VERSION 5.7 ;
  NOWIREEXTENSIONATPIN ON ;
  DIVIDERCHAR "/" ;
  BUSBITCHARS "[]" ;
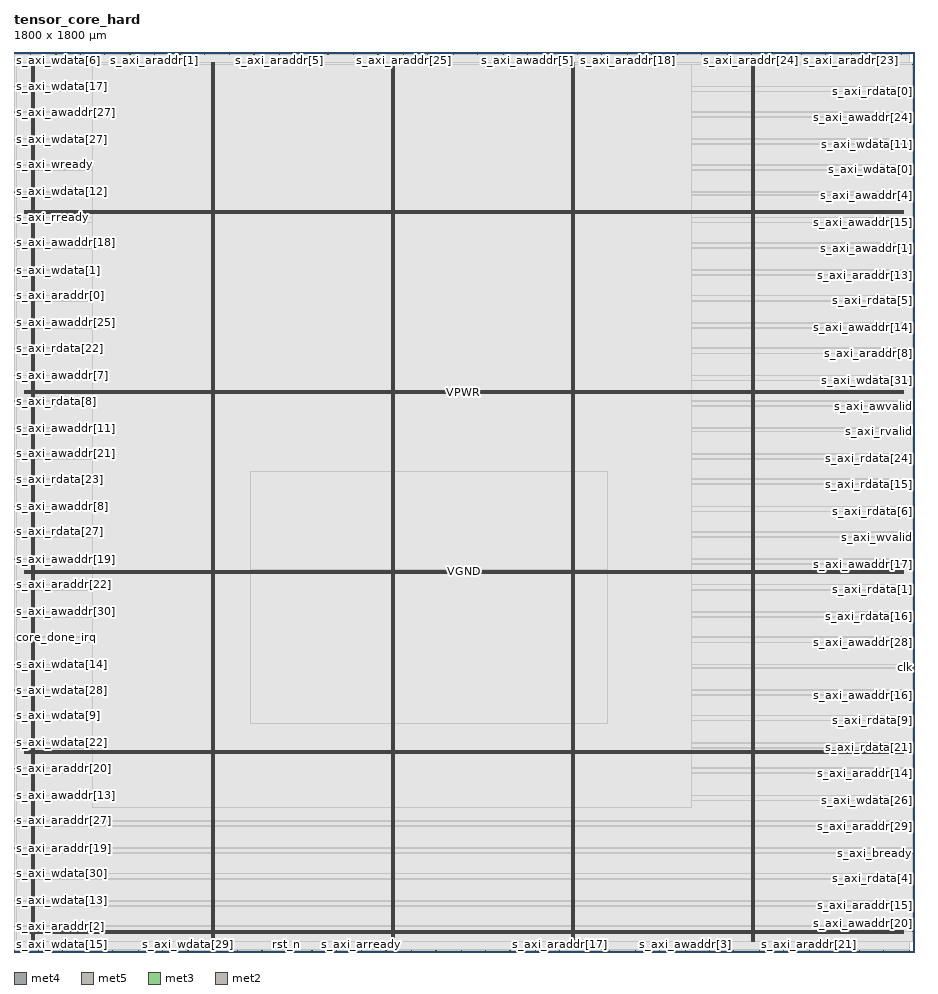
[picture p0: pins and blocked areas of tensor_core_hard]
MACRO tensor_core_hard
  CLASS BLOCK ;
  FOREIGN tensor_core_hard ;
  ORIGIN 0.000 0.000 ;
  SIZE 1800.000 BY 1800.000 ;
  PIN VGND
    DIRECTION INOUT ;
    USE GROUND ;
    PORT
      LAYER met4 ;
        RECT 39.060 21.520 40.660 1779.120 ;
    END
    PORT
      LAYER met4 ;
        RECT 399.060 21.520 400.660 1779.120 ;
    END
    PORT
      LAYER met4 ;
        RECT 759.060 21.520 760.660 1779.120 ;
    END
    PORT
      LAYER met4 ;
        RECT 1119.060 21.520 1120.660 1779.120 ;
    END
    PORT
      LAYER met4 ;
        RECT 1479.060 21.520 1480.660 1779.120 ;
    END
    PORT
      LAYER met5 ;
        RECT 20.000 40.910 1779.980 42.510 ;
    END
    PORT
      LAYER met5 ;
        RECT 20.000 400.910 1779.980 402.510 ;
    END
    PORT
      LAYER met5 ;
        RECT 20.000 760.910 1779.980 762.510 ;
    END
    PORT
      LAYER met5 ;
        RECT 20.000 1120.910 1779.980 1122.510 ;
    END
    PORT
      LAYER met5 ;
        RECT 20.000 1480.910 1779.980 1482.510 ;
    END
  END VGND
  PIN VPWR
    DIRECTION INOUT ;
    USE POWER ;
    PORT
      LAYER met4 ;
        RECT 35.760 21.520 37.360 1779.120 ;
    END
    PORT
      LAYER met4 ;
        RECT 395.760 21.520 397.360 1779.120 ;
    END
    PORT
      LAYER met4 ;
        RECT 755.760 21.520 757.360 1779.120 ;
    END
    PORT
      LAYER met4 ;
        RECT 1115.760 21.520 1117.360 1779.120 ;
    END
    PORT
      LAYER met4 ;
        RECT 1475.760 21.520 1477.360 1779.120 ;
    END
    PORT
      LAYER met5 ;
        RECT 20.000 37.610 1779.980 39.210 ;
    END
    PORT
      LAYER met5 ;
        RECT 20.000 397.610 1779.980 399.210 ;
    END
    PORT
      LAYER met5 ;
        RECT 20.000 757.610 1779.980 759.210 ;
    END
    PORT
      LAYER met5 ;
        RECT 20.000 1117.610 1779.980 1119.210 ;
    END
    PORT
      LAYER met5 ;
        RECT 20.000 1477.610 1779.980 1479.210 ;
    END
  END VPWR
  PIN clk
    DIRECTION INPUT ;
    USE SIGNAL ;
    ANTENNAGATEAREA 1.286700 ;
    ANTENNADIFFAREA 0.434700 ;
    PORT
      LAYER met3 ;
        RECT 1796.000 567.840 1800.000 568.440 ;
    END
  END clk
  PIN core_done_irq
    DIRECTION OUTPUT TRISTATE ;
    USE SIGNAL ;
    ANTENNADIFFAREA 0.795200 ;
    PORT
      LAYER met3 ;
        RECT 0.000 629.040 4.000 629.640 ;
    END
  END core_done_irq
  PIN rst_n
    DIRECTION INPUT ;
    USE SIGNAL ;
    ANTENNAGATEAREA 1.286700 ;
    ANTENNADIFFAREA 0.434700 ;
    PORT
      LAYER met2 ;
        RECT 544.270 0.000 544.550 4.000 ;
    END
  END rst_n
  PIN s_axi_araddr[0]
    DIRECTION INPUT ;
    USE SIGNAL ;
    ANTENNAGATEAREA 0.860700 ;
    ANTENNADIFFAREA 0.434700 ;
    PORT
      LAYER met3 ;
        RECT 0.000 1312.440 4.000 1313.040 ;
    END
  END s_axi_araddr[0]
  PIN s_axi_araddr[10]
    DIRECTION INPUT ;
    USE SIGNAL ;
    PORT
      LAYER met3 ;
        RECT 0.000 1785.040 4.000 1785.640 ;
    END
  END s_axi_araddr[10]
  PIN s_axi_araddr[11]
    DIRECTION INPUT ;
    USE SIGNAL ;
    PORT
      LAYER met2 ;
        RECT 83.810 1796.000 84.090 1800.000 ;
    END
  END s_axi_araddr[11]
  PIN s_axi_araddr[12]
    DIRECTION INPUT ;
    USE SIGNAL ;
    PORT
      LAYER met2 ;
        RECT 495.970 0.000 496.250 4.000 ;
    END
  END s_axi_araddr[12]
  PIN s_axi_araddr[13]
    DIRECTION INPUT ;
    USE SIGNAL ;
    PORT
      LAYER met3 ;
        RECT 1796.000 1353.240 1800.000 1353.840 ;
    END
  END s_axi_araddr[13]
  PIN s_axi_araddr[14]
    DIRECTION INPUT ;
    USE SIGNAL ;
    PORT
      LAYER met3 ;
        RECT 1796.000 357.040 1800.000 357.640 ;
    END
  END s_axi_araddr[14]
  PIN s_axi_araddr[15]
    DIRECTION INPUT ;
    USE SIGNAL ;
    ANTENNAGATEAREA 1.424700 ;
    ANTENNADIFFAREA 0.434700 ;
    PORT
      LAYER met3 ;
        RECT 1796.000 91.840 1800.000 92.440 ;
    END
  END s_axi_araddr[15]
  PIN s_axi_araddr[16]
    DIRECTION INPUT ;
    USE SIGNAL ;
    PORT
      LAYER met2 ;
        RECT 795.430 0.000 795.710 4.000 ;
    END
  END s_axi_araddr[16]
  PIN s_axi_araddr[17]
    DIRECTION INPUT ;
    USE SIGNAL ;
    PORT
      LAYER met2 ;
        RECT 1091.670 0.000 1091.950 4.000 ;
    END
  END s_axi_araddr[17]
  PIN s_axi_araddr[18]
    DIRECTION INPUT ;
    USE SIGNAL ;
    PORT
      LAYER met2 ;
        RECT 1226.910 1796.000 1227.190 1800.000 ;
    END
  END s_axi_araddr[18]
  PIN s_axi_araddr[19]
    DIRECTION INPUT ;
    USE SIGNAL ;
    PORT
      LAYER met3 ;
        RECT 0.000 207.440 4.000 208.040 ;
    END
  END s_axi_araddr[19]
  PIN s_axi_araddr[1]
    DIRECTION INPUT ;
    USE SIGNAL ;
    ANTENNAGATEAREA 0.929700 ;
    ANTENNADIFFAREA 0.434700 ;
    PORT
      LAYER met2 ;
        RECT 280.230 1796.000 280.510 1800.000 ;
    END
  END s_axi_araddr[1]
  PIN s_axi_araddr[20]
    DIRECTION INPUT ;
    USE SIGNAL ;
    PORT
      LAYER met3 ;
        RECT 0.000 367.240 4.000 367.840 ;
    END
  END s_axi_araddr[20]
  PIN s_axi_araddr[21]
    DIRECTION INPUT ;
    USE SIGNAL ;
    PORT
      LAYER met2 ;
        RECT 1590.770 0.000 1591.050 4.000 ;
    END
  END s_axi_araddr[21]
  PIN s_axi_araddr[22]
    DIRECTION INPUT ;
    USE SIGNAL ;
    PORT
      LAYER met3 ;
        RECT 0.000 734.440 4.000 735.040 ;
    END
  END s_axi_araddr[22]
  PIN s_axi_araddr[23]
    DIRECTION INPUT ;
    USE SIGNAL ;
    PORT
      LAYER met2 ;
        RECT 1674.490 1796.000 1674.770 1800.000 ;
    END
  END s_axi_araddr[23]
  PIN s_axi_araddr[24]
    DIRECTION INPUT ;
    USE SIGNAL ;
    PORT
      LAYER met2 ;
        RECT 1474.850 1796.000 1475.130 1800.000 ;
    END
  END s_axi_araddr[24]
  PIN s_axi_araddr[25]
    DIRECTION INPUT ;
    USE SIGNAL ;
    PORT
      LAYER met2 ;
        RECT 779.330 1796.000 779.610 1800.000 ;
    END
  END s_axi_araddr[25]
  PIN s_axi_araddr[26]
    DIRECTION INPUT ;
    USE SIGNAL ;
    PORT
      LAYER met2 ;
        RECT 895.250 0.000 895.530 4.000 ;
    END
  END s_axi_araddr[26]
  PIN s_axi_araddr[27]
    DIRECTION INPUT ;
    USE SIGNAL ;
    PORT
      LAYER met3 ;
        RECT 0.000 261.840 4.000 262.440 ;
    END
  END s_axi_araddr[27]
  PIN s_axi_araddr[28]
    DIRECTION INPUT ;
    USE SIGNAL ;
    PORT
      LAYER met2 ;
        RECT 1622.970 1796.000 1623.250 1800.000 ;
    END
  END s_axi_araddr[28]
  PIN s_axi_araddr[29]
    DIRECTION INPUT ;
    USE SIGNAL ;
    PORT
      LAYER met3 ;
        RECT 1796.000 251.640 1800.000 252.240 ;
    END
  END s_axi_araddr[29]
  PIN s_axi_araddr[2]
    DIRECTION INPUT ;
    USE SIGNAL ;
    ANTENNAGATEAREA 1.424700 ;
    ANTENNADIFFAREA 0.434700 ;
    PORT
      LAYER met3 ;
        RECT 0.000 51.040 4.000 51.640 ;
    END
  END s_axi_araddr[2]
  PIN s_axi_araddr[30]
    DIRECTION INPUT ;
    USE SIGNAL ;
    PORT
      LAYER met2 ;
        RECT 1526.370 1796.000 1526.650 1800.000 ;
    END
  END s_axi_araddr[30]
  PIN s_axi_araddr[31]
    DIRECTION INPUT ;
    USE SIGNAL ;
    PORT
      LAYER met2 ;
        RECT 1722.790 1796.000 1723.070 1800.000 ;
    END
  END s_axi_araddr[31]
  PIN s_axi_araddr[3]
    DIRECTION INPUT ;
    USE SIGNAL ;
    ANTENNAGATEAREA 1.424700 ;
    ANTENNADIFFAREA 0.434700 ;
    PORT
      LAYER met2 ;
        RECT 180.410 1796.000 180.690 1800.000 ;
    END
  END s_axi_araddr[3]
  PIN s_axi_araddr[4]
    DIRECTION INPUT ;
    USE SIGNAL ;
    ANTENNAGATEAREA 1.424700 ;
    ANTENNADIFFAREA 0.434700 ;
    PORT
      LAYER met2 ;
        RECT 132.110 1796.000 132.390 1800.000 ;
    END
  END s_axi_araddr[4]
  PIN s_axi_araddr[5]
    DIRECTION INPUT ;
    USE SIGNAL ;
    ANTENNAGATEAREA 0.631200 ;
    ANTENNADIFFAREA 0.434700 ;
    PORT
      LAYER met2 ;
        RECT 531.390 1796.000 531.670 1800.000 ;
    END
  END s_axi_araddr[5]
  PIN s_axi_araddr[6]
    DIRECTION INPUT ;
    USE SIGNAL ;
    PORT
      LAYER met2 ;
        RECT 1143.190 0.000 1143.470 4.000 ;
    END
  END s_axi_araddr[6]
  PIN s_axi_araddr[7]
    DIRECTION INPUT ;
    USE SIGNAL ;
    PORT
      LAYER met2 ;
        RECT 943.550 0.000 943.830 4.000 ;
    END
  END s_axi_araddr[7]
  PIN s_axi_araddr[8]
    DIRECTION INPUT ;
    USE SIGNAL ;
    PORT
      LAYER met3 ;
        RECT 1796.000 1196.840 1800.000 1197.440 ;
    END
  END s_axi_araddr[8]
  PIN s_axi_araddr[9]
    DIRECTION INPUT ;
    USE SIGNAL ;
    PORT
      LAYER met2 ;
        RECT 1539.250 0.000 1539.530 4.000 ;
    END
  END s_axi_araddr[9]
  PIN s_axi_arready
    DIRECTION OUTPUT TRISTATE ;
    USE SIGNAL ;
    PORT
      LAYER met2 ;
        RECT 695.610 0.000 695.890 4.000 ;
    END
  END s_axi_arready
  PIN s_axi_arvalid
    DIRECTION INPUT ;
    USE SIGNAL ;
    ANTENNAGATEAREA 1.424700 ;
    ANTENNADIFFAREA 0.434700 ;
    PORT
      LAYER met2 ;
        RECT 627.990 1796.000 628.270 1800.000 ;
    END
  END s_axi_arvalid
  PIN s_axi_awaddr[0]
    DIRECTION INPUT ;
    USE SIGNAL ;
    ANTENNAGATEAREA 1.177200 ;
    ANTENNADIFFAREA 0.434700 ;
    PORT
      LAYER met2 ;
        RECT 927.450 1796.000 927.730 1800.000 ;
    END
  END s_axi_awaddr[0]
  PIN s_axi_awaddr[10]
    DIRECTION INPUT ;
    USE SIGNAL ;
    PORT
      LAYER met2 ;
        RECT 1490.950 0.000 1491.230 4.000 ;
    END
  END s_axi_awaddr[10]
  PIN s_axi_awaddr[11]
    DIRECTION INPUT ;
    USE SIGNAL ;
    PORT
      LAYER met3 ;
        RECT 0.000 1047.240 4.000 1047.840 ;
    END
  END s_axi_awaddr[11]
  PIN s_axi_awaddr[12]
    DIRECTION INPUT ;
    USE SIGNAL ;
    ANTENNAGATEAREA 0.860700 ;
    ANTENNADIFFAREA 0.434700 ;
    PORT
      LAYER met2 ;
        RECT 1175.390 1796.000 1175.670 1800.000 ;
    END
  END s_axi_awaddr[12]
  PIN s_axi_awaddr[13]
    DIRECTION INPUT ;
    USE SIGNAL ;
    ANTENNAGATEAREA 1.424700 ;
    ANTENNADIFFAREA 0.434700 ;
    PORT
      LAYER met3 ;
        RECT 0.000 312.840 4.000 313.440 ;
    END
  END s_axi_awaddr[13]
  PIN s_axi_awaddr[14]
    DIRECTION INPUT ;
    USE SIGNAL ;
    ANTENNAGATEAREA 0.593700 ;
    ANTENNADIFFAREA 0.434700 ;
    PORT
      LAYER met3 ;
        RECT 1796.000 1247.840 1800.000 1248.440 ;
    END
  END s_axi_awaddr[14]
  PIN s_axi_awaddr[15]
    DIRECTION INPUT ;
    USE SIGNAL ;
    ANTENNAGATEAREA 0.682200 ;
    ANTENNADIFFAREA 0.434700 ;
    PORT
      LAYER met3 ;
        RECT 1796.000 1458.640 1800.000 1459.240 ;
    END
  END s_axi_awaddr[15]
  PIN s_axi_awaddr[16]
    DIRECTION INPUT ;
    USE SIGNAL ;
    PORT
      LAYER met3 ;
        RECT 1796.000 513.440 1800.000 514.040 ;
    END
  END s_axi_awaddr[16]
  PIN s_axi_awaddr[17]
    DIRECTION INPUT ;
    USE SIGNAL ;
    PORT
      LAYER met3 ;
        RECT 1796.000 775.240 1800.000 775.840 ;
    END
  END s_axi_awaddr[17]
  PIN s_axi_awaddr[18]
    DIRECTION INPUT ;
    USE SIGNAL ;
    PORT
      LAYER met3 ;
        RECT 0.000 1417.840 4.000 1418.440 ;
    END
  END s_axi_awaddr[18]
  PIN s_axi_awaddr[19]
    DIRECTION INPUT ;
    USE SIGNAL ;
    PORT
      LAYER met3 ;
        RECT 0.000 785.440 4.000 786.040 ;
    END
  END s_axi_awaddr[19]
  PIN s_axi_awaddr[1]
    DIRECTION INPUT ;
    USE SIGNAL ;
    ANTENNAGATEAREA 0.682200 ;
    ANTENNADIFFAREA 0.434700 ;
    PORT
      LAYER met3 ;
        RECT 1796.000 1407.640 1800.000 1408.240 ;
    END
  END s_axi_awaddr[1]
  PIN s_axi_awaddr[20]
    DIRECTION INPUT ;
    USE SIGNAL ;
    PORT
      LAYER met3 ;
        RECT 1796.000 40.840 1800.000 41.440 ;
    END
  END s_axi_awaddr[20]
  PIN s_axi_awaddr[21]
    DIRECTION INPUT ;
    USE SIGNAL ;
    PORT
      LAYER met3 ;
        RECT 0.000 996.240 4.000 996.840 ;
    END
  END s_axi_awaddr[21]
  PIN s_axi_awaddr[22]
    DIRECTION INPUT ;
    USE SIGNAL ;
    PORT
      LAYER met2 ;
        RECT 879.150 1796.000 879.430 1800.000 ;
    END
  END s_axi_awaddr[22]
  PIN s_axi_awaddr[23]
    DIRECTION INPUT ;
    USE SIGNAL ;
    PORT
      LAYER met2 ;
        RECT 1426.550 1796.000 1426.830 1800.000 ;
    END
  END s_axi_awaddr[23]
  PIN s_axi_awaddr[24]
    DIRECTION INPUT ;
    USE SIGNAL ;
    PORT
      LAYER met3 ;
        RECT 1796.000 1669.440 1800.000 1670.040 ;
    END
  END s_axi_awaddr[24]
  PIN s_axi_awaddr[25]
    DIRECTION INPUT ;
    USE SIGNAL ;
    PORT
      LAYER met3 ;
        RECT 0.000 1258.040 4.000 1258.640 ;
    END
  END s_axi_awaddr[25]
  PIN s_axi_awaddr[26]
    DIRECTION INPUT ;
    USE SIGNAL ;
    PORT
      LAYER met2 ;
        RECT 447.670 0.000 447.950 4.000 ;
    END
  END s_axi_awaddr[26]
  PIN s_axi_awaddr[27]
    DIRECTION INPUT ;
    USE SIGNAL ;
    PORT
      LAYER met3 ;
        RECT 0.000 1679.640 4.000 1680.240 ;
    END
  END s_axi_awaddr[27]
  PIN s_axi_awaddr[28]
    DIRECTION INPUT ;
    USE SIGNAL ;
    PORT
      LAYER met3 ;
        RECT 1796.000 618.840 1800.000 619.440 ;
    END
  END s_axi_awaddr[28]
  PIN s_axi_awaddr[29]
    DIRECTION INPUT ;
    USE SIGNAL ;
    PORT
      LAYER met2 ;
        RECT 231.930 1796.000 232.210 1800.000 ;
    END
  END s_axi_awaddr[29]
  PIN s_axi_awaddr[2]
    DIRECTION INPUT ;
    USE SIGNAL ;
    ANTENNAGATEAREA 1.424700 ;
    ANTENNADIFFAREA 0.434700 ;
    PORT
      LAYER met2 ;
        RECT 1790.410 0.000 1790.690 4.000 ;
    END
  END s_axi_awaddr[2]
  PIN s_axi_awaddr[30]
    DIRECTION INPUT ;
    USE SIGNAL ;
    PORT
      LAYER met3 ;
        RECT 0.000 680.040 4.000 680.640 ;
    END
  END s_axi_awaddr[30]
  PIN s_axi_awaddr[31]
    DIRECTION INPUT ;
    USE SIGNAL ;
    PORT
      LAYER met2 ;
        RECT 727.810 1796.000 728.090 1800.000 ;
    END
  END s_axi_awaddr[31]
  PIN s_axi_awaddr[3]
    DIRECTION INPUT ;
    USE SIGNAL ;
    ANTENNAGATEAREA 1.424700 ;
    ANTENNADIFFAREA 0.434700 ;
    PORT
      LAYER met2 ;
        RECT 1342.830 0.000 1343.110 4.000 ;
    END
  END s_axi_awaddr[3]
  PIN s_axi_awaddr[4]
    DIRECTION INPUT ;
    USE SIGNAL ;
    ANTENNAGATEAREA 1.424700 ;
    ANTENNADIFFAREA 0.434700 ;
    PORT
      LAYER met3 ;
        RECT 1796.000 1513.040 1800.000 1513.640 ;
    END
  END s_axi_awaddr[4]
  PIN s_axi_awaddr[5]
    DIRECTION INPUT ;
    USE SIGNAL ;
    ANTENNAGATEAREA 1.177200 ;
    ANTENNADIFFAREA 0.434700 ;
    PORT
      LAYER met2 ;
        RECT 1027.270 1796.000 1027.550 1800.000 ;
    END
  END s_axi_awaddr[5]
  PIN s_axi_awaddr[6]
    DIRECTION INPUT ;
    USE SIGNAL ;
    ANTENNAGATEAREA 1.286700 ;
    ANTENNADIFFAREA 0.434700 ;
    PORT
      LAYER met2 ;
        RECT 743.910 0.000 744.190 4.000 ;
    END
  END s_axi_awaddr[6]
  PIN s_axi_awaddr[7]
    DIRECTION INPUT ;
    USE SIGNAL ;
    ANTENNAGATEAREA 0.593700 ;
    ANTENNADIFFAREA 0.434700 ;
    PORT
      LAYER met3 ;
        RECT 0.000 1152.640 4.000 1153.240 ;
    END
  END s_axi_awaddr[7]
  PIN s_axi_awaddr[8]
    DIRECTION INPUT ;
    USE SIGNAL ;
    PORT
      LAYER met3 ;
        RECT 0.000 890.840 4.000 891.440 ;
    END
  END s_axi_awaddr[8]
  PIN s_axi_awaddr[9]
    DIRECTION INPUT ;
    USE SIGNAL ;
    PORT
      LAYER met2 ;
        RECT 579.690 1796.000 579.970 1800.000 ;
    END
  END s_axi_awaddr[9]
  PIN s_axi_awready
    DIRECTION OUTPUT TRISTATE ;
    USE SIGNAL ;
    PORT
      LAYER met2 ;
        RECT 1291.310 0.000 1291.590 4.000 ;
    END
  END s_axi_awready
  PIN s_axi_awvalid
    DIRECTION INPUT ;
    USE SIGNAL ;
    ANTENNAGATEAREA 0.647700 ;
    ANTENNADIFFAREA 0.434700 ;
    PORT
      LAYER met3 ;
        RECT 1796.000 1091.440 1800.000 1092.040 ;
    END
  END s_axi_awvalid
  PIN s_axi_bready
    DIRECTION INPUT ;
    USE SIGNAL ;
    ANTENNAGATEAREA 1.177200 ;
    ANTENNADIFFAREA 0.434700 ;
    PORT
      LAYER met3 ;
        RECT 1796.000 197.240 1800.000 197.840 ;
    END
  END s_axi_bready
  PIN s_axi_bvalid
    DIRECTION OUTPUT TRISTATE ;
    USE SIGNAL ;
    ANTENNADIFFAREA 0.795200 ;
    PORT
      LAYER met2 ;
        RECT 1275.210 1796.000 1275.490 1800.000 ;
    END
  END s_axi_bvalid
  PIN s_axi_rdata[0]
    DIRECTION OUTPUT TRISTATE ;
    USE SIGNAL ;
    ANTENNADIFFAREA 0.795200 ;
    PORT
      LAYER met3 ;
        RECT 1796.000 1720.440 1800.000 1721.040 ;
    END
  END s_axi_rdata[0]
  PIN s_axi_rdata[10]
    DIRECTION OUTPUT TRISTATE ;
    USE SIGNAL ;
    ANTENNADIFFAREA 0.795200 ;
    PORT
      LAYER met2 ;
        RECT 827.630 1796.000 827.910 1800.000 ;
    END
  END s_axi_rdata[10]
  PIN s_axi_rdata[11]
    DIRECTION OUTPUT TRISTATE ;
    USE SIGNAL ;
    ANTENNADIFFAREA 0.795200 ;
    PORT
      LAYER met2 ;
        RECT 48.390 0.000 48.670 4.000 ;
    END
  END s_axi_rdata[11]
  PIN s_axi_rdata[12]
    DIRECTION OUTPUT TRISTATE ;
    USE SIGNAL ;
    ANTENNADIFFAREA 0.795200 ;
    PORT
      LAYER met2 ;
        RECT 248.030 0.000 248.310 4.000 ;
    END
  END s_axi_rdata[12]
  PIN s_axi_rdata[13]
    DIRECTION OUTPUT TRISTATE ;
    USE SIGNAL ;
    ANTENNADIFFAREA 0.795200 ;
    PORT
      LAYER met2 ;
        RECT 1738.890 0.000 1739.170 4.000 ;
    END
  END s_axi_rdata[13]
  PIN s_axi_rdata[14]
    DIRECTION OUTPUT TRISTATE ;
    USE SIGNAL ;
    ANTENNADIFFAREA 0.795200 ;
    PORT
      LAYER met2 ;
        RECT 431.570 1796.000 431.850 1800.000 ;
    END
  END s_axi_rdata[14]
  PIN s_axi_rdata[15]
    DIRECTION OUTPUT TRISTATE ;
    USE SIGNAL ;
    ANTENNADIFFAREA 0.795200 ;
    PORT
      LAYER met3 ;
        RECT 1796.000 935.040 1800.000 935.640 ;
    END
  END s_axi_rdata[15]
  PIN s_axi_rdata[16]
    DIRECTION OUTPUT TRISTATE ;
    USE SIGNAL ;
    ANTENNADIFFAREA 0.795200 ;
    PORT
      LAYER met3 ;
        RECT 1796.000 669.840 1800.000 670.440 ;
    END
  END s_axi_rdata[16]
  PIN s_axi_rdata[17]
    DIRECTION OUTPUT TRISTATE ;
    USE SIGNAL ;
    ANTENNADIFFAREA 0.795200 ;
    PORT
      LAYER met3 ;
        RECT 1796.000 1774.840 1800.000 1775.440 ;
    END
  END s_axi_rdata[17]
  PIN s_axi_rdata[18]
    DIRECTION OUTPUT TRISTATE ;
    USE SIGNAL ;
    ANTENNADIFFAREA 0.795200 ;
    PORT
      LAYER met2 ;
        RECT 148.210 0.000 148.490 4.000 ;
    END
  END s_axi_rdata[18]
  PIN s_axi_rdata[19]
    DIRECTION OUTPUT TRISTATE ;
    USE SIGNAL ;
    ANTENNADIFFAREA 0.795200 ;
    PORT
      LAYER met2 ;
        RECT 380.050 1796.000 380.330 1800.000 ;
    END
  END s_axi_rdata[19]
  PIN s_axi_rdata[1]
    DIRECTION OUTPUT TRISTATE ;
    USE SIGNAL ;
    ANTENNADIFFAREA 0.795200 ;
    PORT
      LAYER met3 ;
        RECT 1796.000 724.240 1800.000 724.840 ;
    END
  END s_axi_rdata[1]
  PIN s_axi_rdata[20]
    DIRECTION OUTPUT TRISTATE ;
    USE SIGNAL ;
    ANTENNADIFFAREA 0.795200 ;
    PORT
      LAYER met2 ;
        RECT 1127.090 1796.000 1127.370 1800.000 ;
    END
  END s_axi_rdata[20]
  PIN s_axi_rdata[21]
    DIRECTION OUTPUT TRISTATE ;
    USE SIGNAL ;
    ANTENNADIFFAREA 0.795200 ;
    PORT
      LAYER met3 ;
        RECT 1796.000 408.040 1800.000 408.640 ;
    END
  END s_axi_rdata[21]
  PIN s_axi_rdata[22]
    DIRECTION OUTPUT TRISTATE ;
    USE SIGNAL ;
    ANTENNADIFFAREA 0.795200 ;
    PORT
      LAYER met3 ;
        RECT 0.000 1207.040 4.000 1207.640 ;
    END
  END s_axi_rdata[22]
  PIN s_axi_rdata[23]
    DIRECTION OUTPUT TRISTATE ;
    USE SIGNAL ;
    ANTENNADIFFAREA 0.795200 ;
    PORT
      LAYER met3 ;
        RECT 0.000 945.240 4.000 945.840 ;
    END
  END s_axi_rdata[23]
  PIN s_axi_rdata[24]
    DIRECTION OUTPUT TRISTATE ;
    USE SIGNAL ;
    ANTENNADIFFAREA 0.795200 ;
    PORT
      LAYER met3 ;
        RECT 1796.000 986.040 1800.000 986.640 ;
    END
  END s_axi_rdata[24]
  PIN s_axi_rdata[25]
    DIRECTION OUTPUT TRISTATE ;
    USE SIGNAL ;
    ANTENNADIFFAREA 0.795200 ;
    PORT
      LAYER met2 ;
        RECT 1774.310 1796.000 1774.590 1800.000 ;
    END
  END s_axi_rdata[25]
  PIN s_axi_rdata[26]
    DIRECTION OUTPUT TRISTATE ;
    USE SIGNAL ;
    ANTENNADIFFAREA 0.795200 ;
    PORT
      LAYER met2 ;
        RECT 396.150 0.000 396.430 4.000 ;
    END
  END s_axi_rdata[26]
  PIN s_axi_rdata[27]
    DIRECTION OUTPUT TRISTATE ;
    USE SIGNAL ;
    ANTENNADIFFAREA 0.795200 ;
    PORT
      LAYER met3 ;
        RECT 0.000 839.840 4.000 840.440 ;
    END
  END s_axi_rdata[27]
  PIN s_axi_rdata[28]
    DIRECTION OUTPUT TRISTATE ;
    USE SIGNAL ;
    ANTENNADIFFAREA 0.795200 ;
    PORT
      LAYER met2 ;
        RECT 1043.370 0.000 1043.650 4.000 ;
    END
  END s_axi_rdata[28]
  PIN s_axi_rdata[29]
    DIRECTION OUTPUT TRISTATE ;
    USE SIGNAL ;
    ANTENNADIFFAREA 0.795200 ;
    PORT
      LAYER met2 ;
        RECT 1690.590 0.000 1690.870 4.000 ;
    END
  END s_axi_rdata[29]
  PIN s_axi_rdata[2]
    DIRECTION OUTPUT TRISTATE ;
    USE SIGNAL ;
    ANTENNADIFFAREA 0.795200 ;
    PORT
      LAYER met2 ;
        RECT 679.510 1796.000 679.790 1800.000 ;
    END
  END s_axi_rdata[2]
  PIN s_axi_rdata[30]
    DIRECTION OUTPUT TRISTATE ;
    USE SIGNAL ;
    ANTENNADIFFAREA 0.795200 ;
    PORT
      LAYER met2 ;
        RECT 1391.130 0.000 1391.410 4.000 ;
    END
  END s_axi_rdata[30]
  PIN s_axi_rdata[31]
    DIRECTION OUTPUT TRISTATE ;
    USE SIGNAL ;
    ANTENNADIFFAREA 0.795200 ;
    PORT
      LAYER met2 ;
        RECT 196.510 0.000 196.790 4.000 ;
    END
  END s_axi_rdata[31]
  PIN s_axi_rdata[3]
    DIRECTION OUTPUT TRISTATE ;
    USE SIGNAL ;
    ANTENNADIFFAREA 0.795200 ;
    PORT
      LAYER met2 ;
        RECT 644.090 0.000 644.370 4.000 ;
    END
  END s_axi_rdata[3]
  PIN s_axi_rdata[4]
    DIRECTION OUTPUT TRISTATE ;
    USE SIGNAL ;
    ANTENNADIFFAREA 0.795200 ;
    PORT
      LAYER met3 ;
        RECT 1796.000 146.240 1800.000 146.840 ;
    END
  END s_axi_rdata[4]
  PIN s_axi_rdata[5]
    DIRECTION OUTPUT TRISTATE ;
    USE SIGNAL ;
    ANTENNADIFFAREA 0.795200 ;
    PORT
      LAYER met3 ;
        RECT 1796.000 1302.240 1800.000 1302.840 ;
    END
  END s_axi_rdata[5]
  PIN s_axi_rdata[6]
    DIRECTION OUTPUT TRISTATE ;
    USE SIGNAL ;
    ANTENNADIFFAREA 0.795200 ;
    PORT
      LAYER met3 ;
        RECT 1796.000 880.640 1800.000 881.240 ;
    END
  END s_axi_rdata[6]
  PIN s_axi_rdata[7]
    DIRECTION OUTPUT TRISTATE ;
    USE SIGNAL ;
    ANTENNADIFFAREA 0.795200 ;
    PORT
      LAYER met2 ;
        RECT 1439.430 0.000 1439.710 4.000 ;
    END
  END s_axi_rdata[7]
  PIN s_axi_rdata[8]
    DIRECTION OUTPUT TRISTATE ;
    USE SIGNAL ;
    ANTENNADIFFAREA 0.795200 ;
    PORT
      LAYER met3 ;
        RECT 0.000 1101.640 4.000 1102.240 ;
    END
  END s_axi_rdata[8]
  PIN s_axi_rdata[9]
    DIRECTION OUTPUT TRISTATE ;
    USE SIGNAL ;
    ANTENNADIFFAREA 0.795200 ;
    PORT
      LAYER met3 ;
        RECT 1796.000 462.440 1800.000 463.040 ;
    END
  END s_axi_rdata[9]
  PIN s_axi_rready
    DIRECTION INPUT ;
    USE SIGNAL ;
    ANTENNAGATEAREA 0.647700 ;
    ANTENNADIFFAREA 0.434700 ;
    PORT
      LAYER met3 ;
        RECT 0.000 1468.840 4.000 1469.440 ;
    END
  END s_axi_rready
  PIN s_axi_rvalid
    DIRECTION OUTPUT TRISTATE ;
    USE SIGNAL ;
    ANTENNADIFFAREA 0.795200 ;
    PORT
      LAYER met3 ;
        RECT 1796.000 1040.440 1800.000 1041.040 ;
    END
  END s_axi_rvalid
  PIN s_axi_wdata[0]
    DIRECTION INPUT ;
    USE SIGNAL ;
    ANTENNAGATEAREA 1.424700 ;
    ANTENNADIFFAREA 0.434700 ;
    PORT
      LAYER met3 ;
        RECT 1796.000 1564.040 1800.000 1564.640 ;
    END
  END s_axi_wdata[0]
  PIN s_axi_wdata[10]
    DIRECTION INPUT ;
    USE SIGNAL ;
    ANTENNAGATEAREA 1.424700 ;
    ANTENNADIFFAREA 0.434700 ;
    PORT
      LAYER met2 ;
        RECT 1639.070 0.000 1639.350 4.000 ;
    END
  END s_axi_wdata[10]
  PIN s_axi_wdata[11]
    DIRECTION INPUT ;
    USE SIGNAL ;
    ANTENNAGATEAREA 1.424700 ;
    ANTENNADIFFAREA 0.434700 ;
    PORT
      LAYER met3 ;
        RECT 1796.000 1615.040 1800.000 1615.640 ;
    END
  END s_axi_wdata[11]
  PIN s_axi_wdata[12]
    DIRECTION INPUT ;
    USE SIGNAL ;
    ANTENNAGATEAREA 1.177200 ;
    ANTENNADIFFAREA 0.434700 ;
    PORT
      LAYER met3 ;
        RECT 0.000 1519.840 4.000 1520.440 ;
    END
  END s_axi_wdata[12]
  PIN s_axi_wdata[13]
    DIRECTION INPUT ;
    USE SIGNAL ;
    ANTENNAGATEAREA 1.286700 ;
    ANTENNADIFFAREA 0.434700 ;
    PORT
      LAYER met3 ;
        RECT 0.000 102.040 4.000 102.640 ;
    END
  END s_axi_wdata[13]
  PIN s_axi_wdata[14]
    DIRECTION INPUT ;
    USE SIGNAL ;
    ANTENNAGATEAREA 0.929700 ;
    ANTENNADIFFAREA 0.434700 ;
    PORT
      LAYER met3 ;
        RECT 0.000 574.640 4.000 575.240 ;
    END
  END s_axi_wdata[14]
  PIN s_axi_wdata[15]
    DIRECTION INPUT ;
    USE SIGNAL ;
    ANTENNAGATEAREA 1.286700 ;
    ANTENNADIFFAREA 0.434700 ;
    PORT
      LAYER met2 ;
        RECT 0.090 0.000 0.370 4.000 ;
    END
  END s_axi_wdata[15]
  PIN s_axi_wdata[16]
    DIRECTION INPUT ;
    USE SIGNAL ;
    ANTENNAGATEAREA 1.424700 ;
    ANTENNADIFFAREA 0.434700 ;
    PORT
      LAYER met2 ;
        RECT 1191.490 0.000 1191.770 4.000 ;
    END
  END s_axi_wdata[16]
  PIN s_axi_wdata[17]
    DIRECTION INPUT ;
    USE SIGNAL ;
    ANTENNAGATEAREA 1.286700 ;
    ANTENNADIFFAREA 0.434700 ;
    PORT
      LAYER met3 ;
        RECT 0.000 1730.640 4.000 1731.240 ;
    END
  END s_axi_wdata[17]
  PIN s_axi_wdata[18]
    DIRECTION INPUT ;
    USE SIGNAL ;
    ANTENNAGATEAREA 1.286700 ;
    ANTENNADIFFAREA 0.434700 ;
    PORT
      LAYER met2 ;
        RECT 479.870 1796.000 480.150 1800.000 ;
    END
  END s_axi_wdata[18]
  PIN s_axi_wdata[19]
    DIRECTION INPUT ;
    USE SIGNAL ;
    ANTENNAGATEAREA 1.424700 ;
    ANTENNADIFFAREA 0.434700 ;
    PORT
      LAYER met2 ;
        RECT 1078.790 1796.000 1079.070 1800.000 ;
    END
  END s_axi_wdata[19]
  PIN s_axi_wdata[1]
    DIRECTION INPUT ;
    USE SIGNAL ;
    ANTENNAGATEAREA 0.929700 ;
    ANTENNADIFFAREA 0.434700 ;
    PORT
      LAYER met3 ;
        RECT 0.000 1363.440 4.000 1364.040 ;
    END
  END s_axi_wdata[1]
  PIN s_axi_wdata[20]
    DIRECTION INPUT ;
    USE SIGNAL ;
    ANTENNAGATEAREA 1.177200 ;
    ANTENNADIFFAREA 0.434700 ;
    PORT
      LAYER met2 ;
        RECT 296.330 0.000 296.610 4.000 ;
    END
  END s_axi_wdata[20]
  PIN s_axi_wdata[21]
    DIRECTION INPUT ;
    USE SIGNAL ;
    ANTENNAGATEAREA 1.177200 ;
    ANTENNADIFFAREA 0.434700 ;
    PORT
      LAYER met2 ;
        RECT 96.690 0.000 96.970 4.000 ;
    END
  END s_axi_wdata[21]
  PIN s_axi_wdata[22]
    DIRECTION INPUT ;
    USE SIGNAL ;
    ANTENNAGATEAREA 0.929700 ;
    ANTENNADIFFAREA 0.434700 ;
    PORT
      LAYER met3 ;
        RECT 0.000 418.240 4.000 418.840 ;
    END
  END s_axi_wdata[22]
  PIN s_axi_wdata[23]
    DIRECTION INPUT ;
    USE SIGNAL ;
    ANTENNAGATEAREA 1.424700 ;
    ANTENNADIFFAREA 0.434700 ;
    PORT
      LAYER met2 ;
        RECT 978.970 1796.000 979.250 1800.000 ;
    END
  END s_axi_wdata[23]
  PIN s_axi_wdata[24]
    DIRECTION INPUT ;
    USE SIGNAL ;
    ANTENNAGATEAREA 1.286700 ;
    ANTENNADIFFAREA 0.434700 ;
    PORT
      LAYER met2 ;
        RECT 843.730 0.000 844.010 4.000 ;
    END
  END s_axi_wdata[24]
  PIN s_axi_wdata[25]
    DIRECTION INPUT ;
    USE SIGNAL ;
    ANTENNAGATEAREA 1.424700 ;
    ANTENNADIFFAREA 0.434700 ;
    PORT
      LAYER met2 ;
        RECT 1574.670 1796.000 1574.950 1800.000 ;
    END
  END s_axi_wdata[25]
  PIN s_axi_wdata[26]
    DIRECTION INPUT ;
    USE SIGNAL ;
    ANTENNAGATEAREA 1.424700 ;
    ANTENNADIFFAREA 0.434700 ;
    PORT
      LAYER met3 ;
        RECT 1796.000 302.640 1800.000 303.240 ;
    END
  END s_axi_wdata[26]
  PIN s_axi_wdata[27]
    DIRECTION INPUT ;
    USE SIGNAL ;
    ANTENNAGATEAREA 1.286700 ;
    ANTENNADIFFAREA 0.434700 ;
    PORT
      LAYER met3 ;
        RECT 0.000 1625.240 4.000 1625.840 ;
    END
  END s_axi_wdata[27]
  PIN s_axi_wdata[28]
    DIRECTION INPUT ;
    USE SIGNAL ;
    ANTENNAGATEAREA 0.929700 ;
    ANTENNADIFFAREA 0.434700 ;
    PORT
      LAYER met3 ;
        RECT 0.000 523.640 4.000 524.240 ;
    END
  END s_axi_wdata[28]
  PIN s_axi_wdata[29]
    DIRECTION INPUT ;
    USE SIGNAL ;
    ANTENNAGATEAREA 1.177200 ;
    ANTENNADIFFAREA 0.434700 ;
    PORT
      LAYER met2 ;
        RECT 347.850 0.000 348.130 4.000 ;
    END
  END s_axi_wdata[29]
  PIN s_axi_wdata[2]
    DIRECTION INPUT ;
    USE SIGNAL ;
    ANTENNAGATEAREA 1.286700 ;
    ANTENNADIFFAREA 0.434700 ;
    PORT
      LAYER met2 ;
        RECT 595.790 0.000 596.070 4.000 ;
    END
  END s_axi_wdata[2]
  PIN s_axi_wdata[30]
    DIRECTION INPUT ;
    USE SIGNAL ;
    ANTENNAGATEAREA 1.286700 ;
    ANTENNADIFFAREA 0.434700 ;
    PORT
      LAYER met3 ;
        RECT 0.000 156.440 4.000 157.040 ;
    END
  END s_axi_wdata[30]
  PIN s_axi_wdata[31]
    DIRECTION INPUT ;
    USE SIGNAL ;
    ANTENNAGATEAREA 1.424700 ;
    ANTENNADIFFAREA 0.434700 ;
    PORT
      LAYER met3 ;
        RECT 1796.000 1142.440 1800.000 1143.040 ;
    END
  END s_axi_wdata[31]
  PIN s_axi_wdata[3]
    DIRECTION INPUT ;
    USE SIGNAL ;
    ANTENNAGATEAREA 1.424700 ;
    ANTENNADIFFAREA 0.434700 ;
    PORT
      LAYER met2 ;
        RECT 991.850 0.000 992.130 4.000 ;
    END
  END s_axi_wdata[3]
  PIN s_axi_wdata[4]
    DIRECTION INPUT ;
    USE SIGNAL ;
    ANTENNAGATEAREA 1.424700 ;
    ANTENNADIFFAREA 0.434700 ;
    PORT
      LAYER met2 ;
        RECT 1375.030 1796.000 1375.310 1800.000 ;
    END
  END s_axi_wdata[4]
  PIN s_axi_wdata[5]
    DIRECTION INPUT ;
    USE SIGNAL ;
    ANTENNAGATEAREA 1.424700 ;
    ANTENNADIFFAREA 0.434700 ;
    PORT
      LAYER met2 ;
        RECT 1326.730 1796.000 1327.010 1800.000 ;
    END
  END s_axi_wdata[5]
  PIN s_axi_wdata[6]
    DIRECTION INPUT ;
    USE SIGNAL ;
    ANTENNAGATEAREA 1.177200 ;
    ANTENNADIFFAREA 0.434700 ;
    PORT
      LAYER met2 ;
        RECT 32.290 1796.000 32.570 1800.000 ;
    END
  END s_axi_wdata[6]
  PIN s_axi_wdata[7]
    DIRECTION INPUT ;
    USE SIGNAL ;
    ANTENNAGATEAREA 1.177200 ;
    ANTENNADIFFAREA 0.434700 ;
    PORT
      LAYER met2 ;
        RECT 331.750 1796.000 332.030 1800.000 ;
    END
  END s_axi_wdata[7]
  PIN s_axi_wdata[8]
    DIRECTION INPUT ;
    USE SIGNAL ;
    ANTENNAGATEAREA 1.424700 ;
    ANTENNADIFFAREA 0.434700 ;
    PORT
      LAYER met2 ;
        RECT 1243.010 0.000 1243.290 4.000 ;
    END
  END s_axi_wdata[8]
  PIN s_axi_wdata[9]
    DIRECTION INPUT ;
    USE SIGNAL ;
    ANTENNAGATEAREA 1.177200 ;
    ANTENNADIFFAREA 0.434700 ;
    PORT
      LAYER met3 ;
        RECT 0.000 472.640 4.000 473.240 ;
    END
  END s_axi_wdata[9]
  PIN s_axi_wready
    DIRECTION OUTPUT TRISTATE ;
    USE SIGNAL ;
    PORT
      LAYER met3 ;
        RECT 0.000 1574.240 4.000 1574.840 ;
    END
  END s_axi_wready
  PIN s_axi_wvalid
    DIRECTION INPUT ;
    USE SIGNAL ;
    ANTENNAGATEAREA 0.682200 ;
    ANTENNADIFFAREA 0.434700 ;
    PORT
      LAYER met3 ;
        RECT 1796.000 829.640 1800.000 830.240 ;
    END
  END s_axi_wvalid
  OBS
      LAYER li1 ;
        RECT 20.240 21.675 1779.740 1778.965 ;
      LAYER met1 ;
        RECT 0.070 20.100 1790.710 1779.120 ;
      LAYER met2 ;
        RECT 0.100 1795.720 32.010 1796.000 ;
        RECT 32.850 1795.720 83.530 1796.000 ;
        RECT 84.370 1795.720 131.830 1796.000 ;
        RECT 132.670 1795.720 180.130 1796.000 ;
        RECT 180.970 1795.720 231.650 1796.000 ;
        RECT 232.490 1795.720 279.950 1796.000 ;
        RECT 280.790 1795.720 331.470 1796.000 ;
        RECT 332.310 1795.720 379.770 1796.000 ;
        RECT 380.610 1795.720 431.290 1796.000 ;
        RECT 432.130 1795.720 479.590 1796.000 ;
        RECT 480.430 1795.720 531.110 1796.000 ;
        RECT 531.950 1795.720 579.410 1796.000 ;
        RECT 580.250 1795.720 627.710 1796.000 ;
        RECT 628.550 1795.720 679.230 1796.000 ;
        RECT 680.070 1795.720 727.530 1796.000 ;
        RECT 728.370 1795.720 779.050 1796.000 ;
        RECT 779.890 1795.720 827.350 1796.000 ;
        RECT 828.190 1795.720 878.870 1796.000 ;
        RECT 879.710 1795.720 927.170 1796.000 ;
        RECT 928.010 1795.720 978.690 1796.000 ;
        RECT 979.530 1795.720 1026.990 1796.000 ;
        RECT 1027.830 1795.720 1078.510 1796.000 ;
        RECT 1079.350 1795.720 1126.810 1796.000 ;
        RECT 1127.650 1795.720 1175.110 1796.000 ;
        RECT 1175.950 1795.720 1226.630 1796.000 ;
        RECT 1227.470 1795.720 1274.930 1796.000 ;
        RECT 1275.770 1795.720 1326.450 1796.000 ;
        RECT 1327.290 1795.720 1374.750 1796.000 ;
        RECT 1375.590 1795.720 1426.270 1796.000 ;
        RECT 1427.110 1795.720 1474.570 1796.000 ;
        RECT 1475.410 1795.720 1526.090 1796.000 ;
        RECT 1526.930 1795.720 1574.390 1796.000 ;
        RECT 1575.230 1795.720 1622.690 1796.000 ;
        RECT 1623.530 1795.720 1674.210 1796.000 ;
        RECT 1675.050 1795.720 1722.510 1796.000 ;
        RECT 1723.350 1795.720 1774.030 1796.000 ;
        RECT 1774.870 1795.720 1790.680 1796.000 ;
        RECT 0.100 4.280 1790.680 1795.720 ;
        RECT 0.650 4.000 48.110 4.280 ;
        RECT 48.950 4.000 96.410 4.280 ;
        RECT 97.250 4.000 147.930 4.280 ;
        RECT 148.770 4.000 196.230 4.280 ;
        RECT 197.070 4.000 247.750 4.280 ;
        RECT 248.590 4.000 296.050 4.280 ;
        RECT 296.890 4.000 347.570 4.280 ;
        RECT 348.410 4.000 395.870 4.280 ;
        RECT 396.710 4.000 447.390 4.280 ;
        RECT 448.230 4.000 495.690 4.280 ;
        RECT 496.530 4.000 543.990 4.280 ;
        RECT 544.830 4.000 595.510 4.280 ;
        RECT 596.350 4.000 643.810 4.280 ;
        RECT 644.650 4.000 695.330 4.280 ;
        RECT 696.170 4.000 743.630 4.280 ;
        RECT 744.470 4.000 795.150 4.280 ;
        RECT 795.990 4.000 843.450 4.280 ;
        RECT 844.290 4.000 894.970 4.280 ;
        RECT 895.810 4.000 943.270 4.280 ;
        RECT 944.110 4.000 991.570 4.280 ;
        RECT 992.410 4.000 1043.090 4.280 ;
        RECT 1043.930 4.000 1091.390 4.280 ;
        RECT 1092.230 4.000 1142.910 4.280 ;
        RECT 1143.750 4.000 1191.210 4.280 ;
        RECT 1192.050 4.000 1242.730 4.280 ;
        RECT 1243.570 4.000 1291.030 4.280 ;
        RECT 1291.870 4.000 1342.550 4.280 ;
        RECT 1343.390 4.000 1390.850 4.280 ;
        RECT 1391.690 4.000 1439.150 4.280 ;
        RECT 1439.990 4.000 1490.670 4.280 ;
        RECT 1491.510 4.000 1538.970 4.280 ;
        RECT 1539.810 4.000 1590.490 4.280 ;
        RECT 1591.330 4.000 1638.790 4.280 ;
        RECT 1639.630 4.000 1690.310 4.280 ;
        RECT 1691.150 4.000 1738.610 4.280 ;
        RECT 1739.450 4.000 1790.130 4.280 ;
      LAYER met3 ;
        RECT 4.000 1775.840 1796.000 1779.045 ;
        RECT 4.000 1774.440 1795.600 1775.840 ;
        RECT 4.000 1731.640 1796.000 1774.440 ;
        RECT 4.400 1730.240 1796.000 1731.640 ;
        RECT 4.000 1721.440 1796.000 1730.240 ;
        RECT 4.000 1720.040 1795.600 1721.440 ;
        RECT 4.000 1680.640 1796.000 1720.040 ;
        RECT 4.400 1679.240 1796.000 1680.640 ;
        RECT 4.000 1670.440 1796.000 1679.240 ;
        RECT 4.000 1669.040 1795.600 1670.440 ;
        RECT 4.000 1626.240 1796.000 1669.040 ;
        RECT 4.400 1624.840 1796.000 1626.240 ;
        RECT 4.000 1616.040 1796.000 1624.840 ;
        RECT 4.000 1614.640 1795.600 1616.040 ;
        RECT 4.000 1575.240 1796.000 1614.640 ;
        RECT 4.400 1573.840 1796.000 1575.240 ;
        RECT 4.000 1565.040 1796.000 1573.840 ;
        RECT 4.000 1563.640 1795.600 1565.040 ;
        RECT 4.000 1520.840 1796.000 1563.640 ;
        RECT 4.400 1519.440 1796.000 1520.840 ;
        RECT 4.000 1514.040 1796.000 1519.440 ;
        RECT 4.000 1512.640 1795.600 1514.040 ;
        RECT 4.000 1469.840 1796.000 1512.640 ;
        RECT 4.400 1468.440 1796.000 1469.840 ;
        RECT 4.000 1459.640 1796.000 1468.440 ;
        RECT 4.000 1458.240 1795.600 1459.640 ;
        RECT 4.000 1418.840 1796.000 1458.240 ;
        RECT 4.400 1417.440 1796.000 1418.840 ;
        RECT 4.000 1408.640 1796.000 1417.440 ;
        RECT 4.000 1407.240 1795.600 1408.640 ;
        RECT 4.000 1364.440 1796.000 1407.240 ;
        RECT 4.400 1363.040 1796.000 1364.440 ;
        RECT 4.000 1354.240 1796.000 1363.040 ;
        RECT 4.000 1352.840 1795.600 1354.240 ;
        RECT 4.000 1313.440 1796.000 1352.840 ;
        RECT 4.400 1312.040 1796.000 1313.440 ;
        RECT 4.000 1303.240 1796.000 1312.040 ;
        RECT 4.000 1301.840 1795.600 1303.240 ;
        RECT 4.000 1259.040 1796.000 1301.840 ;
        RECT 4.400 1257.640 1796.000 1259.040 ;
        RECT 4.000 1248.840 1796.000 1257.640 ;
        RECT 4.000 1247.440 1795.600 1248.840 ;
        RECT 4.000 1208.040 1796.000 1247.440 ;
        RECT 4.400 1206.640 1796.000 1208.040 ;
        RECT 4.000 1197.840 1796.000 1206.640 ;
        RECT 4.000 1196.440 1795.600 1197.840 ;
        RECT 4.000 1153.640 1796.000 1196.440 ;
        RECT 4.400 1152.240 1796.000 1153.640 ;
        RECT 4.000 1143.440 1796.000 1152.240 ;
        RECT 4.000 1142.040 1795.600 1143.440 ;
        RECT 4.000 1102.640 1796.000 1142.040 ;
        RECT 4.400 1101.240 1796.000 1102.640 ;
        RECT 4.000 1092.440 1796.000 1101.240 ;
        RECT 4.000 1091.040 1795.600 1092.440 ;
        RECT 4.000 1048.240 1796.000 1091.040 ;
        RECT 4.400 1046.840 1796.000 1048.240 ;
        RECT 4.000 1041.440 1796.000 1046.840 ;
        RECT 4.000 1040.040 1795.600 1041.440 ;
        RECT 4.000 997.240 1796.000 1040.040 ;
        RECT 4.400 995.840 1796.000 997.240 ;
        RECT 4.000 987.040 1796.000 995.840 ;
        RECT 4.000 985.640 1795.600 987.040 ;
        RECT 4.000 946.240 1796.000 985.640 ;
        RECT 4.400 944.840 1796.000 946.240 ;
        RECT 4.000 936.040 1796.000 944.840 ;
        RECT 4.000 934.640 1795.600 936.040 ;
        RECT 4.000 891.840 1796.000 934.640 ;
        RECT 4.400 890.440 1796.000 891.840 ;
        RECT 4.000 881.640 1796.000 890.440 ;
        RECT 4.000 880.240 1795.600 881.640 ;
        RECT 4.000 840.840 1796.000 880.240 ;
        RECT 4.400 839.440 1796.000 840.840 ;
        RECT 4.000 830.640 1796.000 839.440 ;
        RECT 4.000 829.240 1795.600 830.640 ;
        RECT 4.000 786.440 1796.000 829.240 ;
        RECT 4.400 785.040 1796.000 786.440 ;
        RECT 4.000 776.240 1796.000 785.040 ;
        RECT 4.000 774.840 1795.600 776.240 ;
        RECT 4.000 735.440 1796.000 774.840 ;
        RECT 4.400 734.040 1796.000 735.440 ;
        RECT 4.000 725.240 1796.000 734.040 ;
        RECT 4.000 723.840 1795.600 725.240 ;
        RECT 4.000 681.040 1796.000 723.840 ;
        RECT 4.400 679.640 1796.000 681.040 ;
        RECT 4.000 670.840 1796.000 679.640 ;
        RECT 4.000 669.440 1795.600 670.840 ;
        RECT 4.000 630.040 1796.000 669.440 ;
        RECT 4.400 628.640 1796.000 630.040 ;
        RECT 4.000 619.840 1796.000 628.640 ;
        RECT 4.000 618.440 1795.600 619.840 ;
        RECT 4.000 575.640 1796.000 618.440 ;
        RECT 4.400 574.240 1796.000 575.640 ;
        RECT 4.000 568.840 1796.000 574.240 ;
        RECT 4.000 567.440 1795.600 568.840 ;
        RECT 4.000 524.640 1796.000 567.440 ;
        RECT 4.400 523.240 1796.000 524.640 ;
        RECT 4.000 514.440 1796.000 523.240 ;
        RECT 4.000 513.040 1795.600 514.440 ;
        RECT 4.000 473.640 1796.000 513.040 ;
        RECT 4.400 472.240 1796.000 473.640 ;
        RECT 4.000 463.440 1796.000 472.240 ;
        RECT 4.000 462.040 1795.600 463.440 ;
        RECT 4.000 419.240 1796.000 462.040 ;
        RECT 4.400 417.840 1796.000 419.240 ;
        RECT 4.000 409.040 1796.000 417.840 ;
        RECT 4.000 407.640 1795.600 409.040 ;
        RECT 4.000 368.240 1796.000 407.640 ;
        RECT 4.400 366.840 1796.000 368.240 ;
        RECT 4.000 358.040 1796.000 366.840 ;
        RECT 4.000 356.640 1795.600 358.040 ;
        RECT 4.000 313.840 1796.000 356.640 ;
        RECT 4.400 312.440 1796.000 313.840 ;
        RECT 4.000 303.640 1796.000 312.440 ;
        RECT 4.000 302.240 1795.600 303.640 ;
        RECT 4.000 262.840 1796.000 302.240 ;
        RECT 4.400 261.440 1796.000 262.840 ;
        RECT 4.000 252.640 1796.000 261.440 ;
        RECT 4.000 251.240 1795.600 252.640 ;
        RECT 4.000 208.440 1796.000 251.240 ;
        RECT 4.400 207.040 1796.000 208.440 ;
        RECT 4.000 198.240 1796.000 207.040 ;
        RECT 4.000 196.840 1795.600 198.240 ;
        RECT 4.000 157.440 1796.000 196.840 ;
        RECT 4.400 156.040 1796.000 157.440 ;
        RECT 4.000 147.240 1796.000 156.040 ;
        RECT 4.000 145.840 1795.600 147.240 ;
        RECT 4.000 103.040 1796.000 145.840 ;
        RECT 4.400 101.640 1796.000 103.040 ;
        RECT 4.000 92.840 1796.000 101.640 ;
        RECT 4.000 91.440 1795.600 92.840 ;
        RECT 4.000 52.040 1796.000 91.440 ;
        RECT 4.400 50.640 1796.000 52.040 ;
        RECT 4.000 41.840 1796.000 50.640 ;
        RECT 4.000 40.440 1795.600 41.840 ;
        RECT 4.000 21.595 1796.000 40.440 ;
      LAYER met4 ;
        RECT 157.615 289.175 395.360 1775.985 ;
        RECT 397.760 289.175 398.660 1775.985 ;
        RECT 401.060 289.175 755.360 1775.985 ;
        RECT 757.760 289.175 758.660 1775.985 ;
        RECT 761.060 289.175 1115.360 1775.985 ;
        RECT 1117.760 289.175 1118.660 1775.985 ;
        RECT 1121.060 289.175 1354.865 1775.985 ;
      LAYER met5 ;
        RECT 472.540 764.110 1186.220 961.300 ;
        RECT 472.540 456.500 1186.220 756.010 ;
  END
END tensor_core_hard
END LIBRARY

